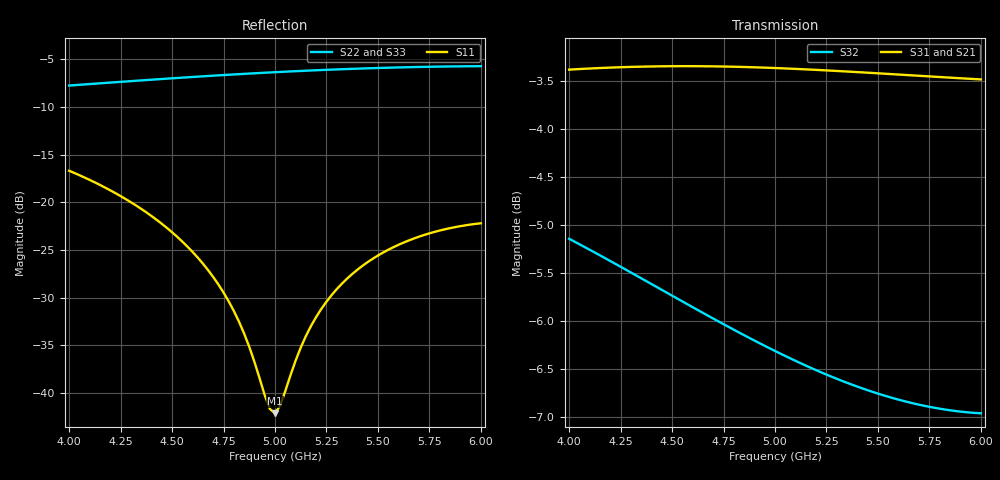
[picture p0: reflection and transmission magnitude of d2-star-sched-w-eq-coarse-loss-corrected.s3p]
! yapnr Order 0 prediction d2-star-sched-w-eq-coarse: predictions/D2/runs/d2-star-sched/coarse_dense.s3p, loss-corrected
! substrate W-eq; coupon model OSHPARK-4L-FR408HR; correction: ratio (port line)
! |S21|, |S31| (and S12, S13) scaled, phases kept; 50 ohm, e^(+jwt)
# GHz S RI R 50
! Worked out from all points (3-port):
!   81 points, 4 GHz to 6 GHz, reference 50 ohm
!   strongest paths, dB at 4 GHz, 4.5 GHz, 5 GHz, 5.5 GHz, 6 GHz:
!     S31: -3.4, -3.3, -3.4, -3.4, -3.5
!     S21: -3.4, -3.3, -3.4, -3.4, -3.5
!     S32: -5.1, -5.7, -6.3, -6.8, -7.0
!   lowest |S11| = -42.1 dB at 5 GHz (marker M1), VSWR 1.02, Z = 49.5 + j0.629 ohm
!   |S11| at or under -10 dB: start of sweep to end of sweep
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4  0.0358 0.142  -0.6577 -0.1623  -0.6577 -0.1623
   -0.6576 -0.1629  0.353 -0.2078  -0.4537 0.3163
   -0.6576 -0.1629  -0.4537 0.3163  0.353 -0.2078
4.375  0.0405 0.0789  -0.6784 0.0371  -0.6784 0.0371
       -0.679 0.036  0.2747 -0.3406  -0.309 0.4252
       -0.679 0.036  -0.309 0.4252  0.2747 -0.3406
4.65  0.0266 0.0396  -0.6539 0.1837  -0.6539 0.1837
      -0.6553 0.1827  0.1905 -0.4163  -0.194 0.4673
      -0.6553 0.1827  -0.194 0.4673  0.1905 -0.4163
4.825  0.0123 0.0203  -0.6211 0.2728  -0.6211 0.2728
       -0.623 0.272  0.1281 -0.4521  -0.1215 0.4791
       -0.623 0.272  -0.1215 0.4791  0.1281 -0.4521
4.975  -0.00209 0.00799  -0.5831 0.3447  -0.5831 0.3447
       -0.5852 0.3442  0.0707 -0.4743  -0.0613 0.481
       -0.5852 0.3442  -0.0613 0.481  0.0707 -0.4743
5  -0.0046 0.00634  -0.5759 0.3562  -0.5759 0.3562
   -0.5781 0.3557  0.0609 -0.4772  -0.0515 0.4806
   -0.5781 0.3557  -0.0515 0.4806  0.0609 -0.4772
5.175  -0.0224 -0.00196  -0.5192 0.4321  -0.5192 0.4321
       -0.5217 0.4322  -0.00917 -0.4911  0.015 0.4734
       -0.5217 0.4322  0.015 0.4734  -0.00917 -0.4911
5.35  -0.0395 -0.00487  -0.4525 0.499  -0.4525 0.499
      -0.4552 0.4997  -0.0802 -0.4934  0.0773 0.4588
      -0.4552 0.4997  0.0773 0.4588  -0.0802 -0.4934
5.625  -0.0616 -0.000359  -0.3311 0.583  -0.3311 0.583
       -0.3335 0.5848  -0.189 -0.4741  0.1664 0.4237
       -0.3335 0.5848  0.1664 0.4237  -0.189 -0.4741
6  -0.076 0.016  -0.1426 0.6509  -0.1426 0.6509
   -0.1438 0.6539  -0.3206 -0.4062  0.2713 0.3572
   -0.1438 0.6539  0.2713 0.3572  -0.3206 -0.4062
